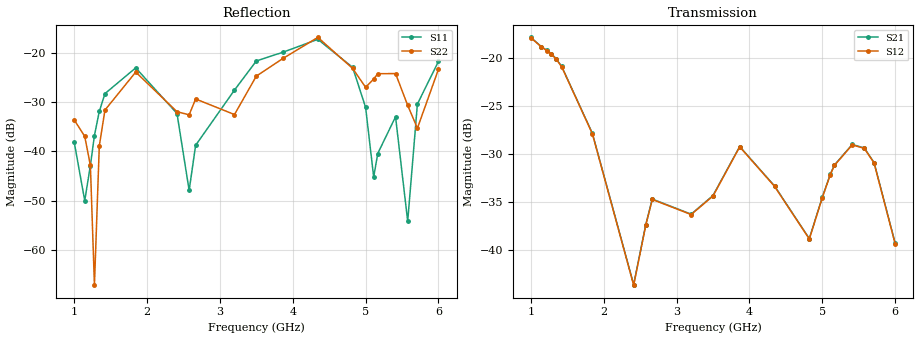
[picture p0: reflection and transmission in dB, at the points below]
!Agilent Technologies,E8364B,MY43040528,A.07.50.67
!Agilent E8364B: A.07.50.67
!Date: Sunday, March 01, 2026 17:08:27
!Correction: S11(Full 2 Port(1,2))
!S21(Full 2 Port(1,2))
!S12(Full 2 Port(1,2))
!S22(Full 2 Port(1,2))
!S2P File: Measurements: S11, S21, S12, S22:
# Hz S  dB  R 50
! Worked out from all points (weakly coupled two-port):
!   451 points, 1 GHz to 6 GHz, reference 50 ohm
!   highest |S21| = -17.82 dB at 1 GHz (marker M1); lowest = -43.6 dB at 2.411 GHz (marker M2)
!   lowest |S11| = -54.2 dB at 5.578 GHz (marker M3), VSWR 1.00, Z = 50.1 - j0.143 ohm
!   |S11| at or under -10 dB: start of sweep to end of sweep
!   |S22| runs from -67.2 to -16.7 dB; largest |S21 - S12| = 0.00062
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1e9  -38.10 7.1  -17.82 28.4  -17.86 28.5  -33.59 -2.7
1.144444e9  -50.02 -61.2  -18.79 -14.5  -18.82 -14.4  -36.93 -5.8
1.222222e9  -42.88 -124.1  -19.17 -38.8  -19.21 -38.7  -42.85 -12.5
1.277778e9  -36.77 -141.2  -19.50 -56.9  -19.54 -56.9  -67.21 39.1
1.344444e9  -31.86 -157.2  -20.02 -79.3  -20.06 -79.2  -38.88 122.9
1.422222e9  -28.24 -177.7  -20.84 -105.6  -20.87 -105.6  -31.59 104.4
1.844444e9  -23.00 88.8  -27.82 119.2  -27.86 119.3  -23.86 -5.2
2.411111e9  -32.29 -15.6  -43.57 -128.5  -43.62 -128.4  -31.92 -87.3
2.577778e9  -47.94 -134.1  -37.31 109.8  -37.36 109.8  -32.56 -57.0
2.666667e9  -38.76 138.2  -34.66 67.6  -34.70 67.7  -29.33 -59.4
3.2e9  -27.52 117.7  -36.23 -127.5  -36.27 -127.5  -32.50 -120.9
3.5e9  -21.60 67.7  -34.29 -156.9  -34.34 -156.9  -24.68 -128.5
3.866667e9  -19.81 27.6  -29.19 74.4  -29.22 74.6  -21.08 -164.5
4.344444e9  -17.20 -48.4  -33.29 -102.1  -33.33 -102.1  -16.80 111.5
4.822222e9  -22.90 -140.2  -38.78 21.3  -38.82 21.4  -23.12 31.3
5e9  -31.05 -175.1  -34.48 -80.5  -34.52 -80.4  -26.96 39.6
5.111111e9  -45.24 -142.2  -32.06 -134.0  -32.10 -134.0  -25.27 44.5
5.166667e9  -40.43 -72.8  -31.12 -159.4  -31.16 -159.3  -24.19 39.0
5.411111e9  -32.95 -113.0  -28.97 93.6  -29.01 93.6  -24.16 -9.8
5.577778e9  -54.22 -47.0  -29.34 22.5  -29.39 22.5  -30.64 -38.3
5.711111e9  -30.36 -15.7  -30.86 -33.1  -30.90 -33.1  -35.28 27.0
6e9  -21.69 -75.2  -39.24 -136.3  -39.29 -136.3  -23.30 -0.7
